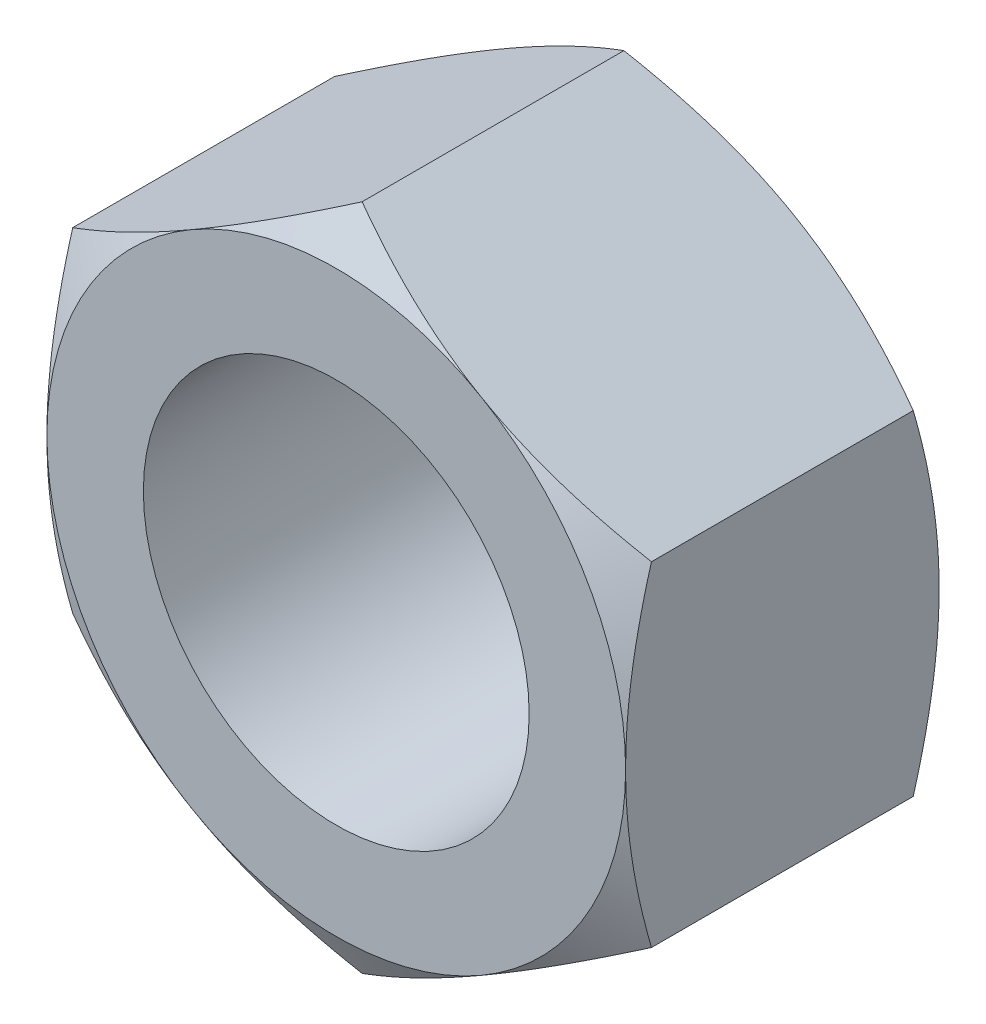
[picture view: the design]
ISO-10303-21;
HEADER;
FILE_DESCRIPTION(('STEP AP214'),'2;1');
FILE_NAME('part.step','',(''),(''),'','','');
FILE_SCHEMA(('AUTOMOTIVE_DESIGN { 1 0 10303 214 1 1 1 1 }'));
ENDSEC;
DATA;
#1=APPLICATION_CONTEXT('core data for automotive mechanical design processes');
#2=APPLICATION_PROTOCOL_DEFINITION('international standard','automotive_design',2000,#1);
#3=PRODUCT_CONTEXT('',#1,'mechanical');
#4=PRODUCT('Part','Part','',(#3));
#5=PRODUCT_RELATED_PRODUCT_CATEGORY('part','',(#4));
#6=PRODUCT_DEFINITION_FORMATION('','',#4);
#7=PRODUCT_DEFINITION_CONTEXT('part definition',#1,'design');
#8=PRODUCT_DEFINITION('design','',#6,#7);
#9=PRODUCT_DEFINITION_SHAPE('','',#8);
#10=(LENGTH_UNIT() NAMED_UNIT(*) SI_UNIT(.MILLI.,.METRE.));
#11=(NAMED_UNIT(*) PLANE_ANGLE_UNIT() SI_UNIT($,.RADIAN.));
#12=(NAMED_UNIT(*) SI_UNIT($,.STERADIAN.) SOLID_ANGLE_UNIT());
#13=UNCERTAINTY_MEASURE_WITH_UNIT(LENGTH_MEASURE(1.E-05),#10,'distance_accuracy_value','');
#14=(GEOMETRIC_REPRESENTATION_CONTEXT(3) GLOBAL_UNCERTAINTY_ASSIGNED_CONTEXT((#13)) GLOBAL_UNIT_ASSIGNED_CONTEXT((#10,
#11,#12)) REPRESENTATION_CONTEXT('',''));
#15=CARTESIAN_POINT('',(0.,0.,0.));
#16=DIRECTION('',(0.,0.,1.));
#17=DIRECTION('',(1.,0.,0.));
#18=AXIS2_PLACEMENT_3D('',#15,#16,#17);
#19=CARTESIAN_POINT('',(-12.,20.7846096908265,0.));
#20=DIRECTION('',(0.,0.,-1.));
#21=DIRECTION('',(-1.,0.,0.));
#22=AXIS2_PLACEMENT_3D('',#19,#20,#21);
#23=PLANE('',#22);
#24=CARTESIAN_POINT('',(0.,0.,0.));
#25=DIRECTION('',(0.,0.,1.));
#26=DIRECTION('',(1.,0.,0.));
#27=AXIS2_PLACEMENT_3D('',#24,#25,#26);
#28=CIRCLE('',#27,8.);
#29=CARTESIAN_POINT('',(8.,0.,0.));
#30=VERTEX_POINT('',#29);
#31=EDGE_CURVE('E318',#30,#30,#28,.T.);
#32=ORIENTED_EDGE('',*,*,#31,.F.);
#33=EDGE_LOOP('',(#32));
#34=FACE_BOUND('',#33,.T.);
#35=CARTESIAN_POINT('',(0.,0.,0.));
#36=DIRECTION('',(0.,0.,-1.));
#37=DIRECTION('',(-1.,0.,0.));
#38=AXIS2_PLACEMENT_3D('',#35,#36,#37);
#39=CIRCLE('',#38,12.);
#40=CARTESIAN_POINT('',(-12.,0.,0.));
#41=VERTEX_POINT('',#40);
#42=CARTESIAN_POINT('',(-6.,10.3923048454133,0.));
#43=VERTEX_POINT('',#42);
#44=EDGE_CURVE('E326',#41,#43,#39,.T.);
#45=ORIENTED_EDGE('',*,*,#44,.F.);
#46=CARTESIAN_POINT('',(0.,0.,0.));
#47=DIRECTION('',(0.,0.,-1.));
#48=DIRECTION('',(-1.,0.,0.));
#49=AXIS2_PLACEMENT_3D('',#46,#47,#48);
#50=CIRCLE('',#49,12.);
#51=CARTESIAN_POINT('',(-5.99999999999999,-10.3923048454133,0.));
#52=VERTEX_POINT('',#51);
#53=EDGE_CURVE('E148',#41,#52,#50,.F.);
#54=ORIENTED_EDGE('',*,*,#53,.T.);
#55=CARTESIAN_POINT('',(5.99999999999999,-10.3923048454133,0.));
#56=VERTEX_POINT('',#55);
#57=EDGE_CURVE('E250',#52,#56,#50,.F.);
#58=ORIENTED_EDGE('',*,*,#57,.T.);
#59=CARTESIAN_POINT('',(12.,0.,0.));
#60=VERTEX_POINT('',#59);
#61=EDGE_CURVE('E151',#56,#60,#50,.F.);
#62=ORIENTED_EDGE('',*,*,#61,.T.);
#63=CARTESIAN_POINT('',(5.99999999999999,10.3923048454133,0.));
#64=VERTEX_POINT('',#63);
#65=EDGE_CURVE('E126',#60,#64,#50,.F.);
#66=ORIENTED_EDGE('',*,*,#65,.T.);
#67=EDGE_CURVE('E139',#64,#43,#50,.F.);
#68=ORIENTED_EDGE('',*,*,#67,.T.);
#69=EDGE_LOOP('',(#45,#54,#58,#62,#66,#68));
#70=FACE_BOUND('',#69,.T.);
#71=ADVANCED_FACE('F31',(#34,#70),#23,.F.);
#72=CARTESIAN_POINT('',(0.,0.,0.));
#73=DIRECTION('',(0.,0.,-1.));
#74=DIRECTION('',(-1.,0.,0.));
#75=AXIS2_PLACEMENT_3D('',#72,#73,#74);
#76=CONICAL_SURFACE('',#75,12.,1.0471975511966);
#77=CARTESIAN_POINT('',(-12.,-18.6784608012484,-5.8895565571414));
#78=CARTESIAN_POINT('',(-12.,-18.4160847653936,-5.76211140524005));
#79=CARTESIAN_POINT('',(-12.,-18.1534026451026,-5.63529669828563));
#80=CARTESIAN_POINT('',(-12.,-17.6273623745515,-5.38307084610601));
#81=CARTESIAN_POINT('',(-12.,-17.3640042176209,-5.25765971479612));
#82=CARTESIAN_POINT('',(-12.,-16.5727506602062,-4.8837130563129));
#83=CARTESIAN_POINT('',(-12.,-16.0437527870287,-4.63750158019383));
#84=CARTESIAN_POINT('',(-12.,-14.9793937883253,-4.15144188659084));
#85=CARTESIAN_POINT('',(-12.,-14.444013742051,-3.91163500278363));
#86=CARTESIAN_POINT('',(-12.,-13.3690190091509,-3.44174237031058));
#87=CARTESIAN_POINT('',(-12.,-12.82940452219,-3.21165616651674));
#88=CARTESIAN_POINT('',(-12.,-11.7275565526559,-2.75653640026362));
#89=CARTESIAN_POINT('',(-12.,-11.1651555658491,-2.53190627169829));
#90=CARTESIAN_POINT('',(-12.,-10.0337957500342,-2.09948087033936));
#91=CARTESIAN_POINT('',(-12.,-9.46483619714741,-1.89168747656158));
#92=CARTESIAN_POINT('',(-12.,-8.32051465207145,-1.49834244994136));
#93=CARTESIAN_POINT('',(-12.,-7.7451680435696,-1.31274641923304));
#94=CARTESIAN_POINT('',(-12.,-6.58616859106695,-0.969694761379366));
#95=CARTESIAN_POINT('',(-12.,-6.00251840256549,-0.812230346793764));
#96=CARTESIAN_POINT('',(-12.,-5.1222851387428,-0.603216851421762));
#97=CARTESIAN_POINT('',(-12.,-4.82887752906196,-0.538215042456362));
#98=CARTESIAN_POINT('',(-12.,-4.24004478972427,-0.418045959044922));
#99=CARTESIAN_POINT('',(-12.,-3.94461970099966,-0.362878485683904));
#100=CARTESIAN_POINT('',(-12.,-3.35195163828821,-0.263347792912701));
#101=CARTESIAN_POINT('',(-12.,-3.05470869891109,-0.2189843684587));
#102=CARTESIAN_POINT('',(-12.,-2.45871340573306,-0.141943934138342));
#103=CARTESIAN_POINT('',(-12.,-2.15996111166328,-0.10926646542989));
#104=CARTESIAN_POINT('',(-12.,-1.56529773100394,-0.0566609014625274));
#105=CARTESIAN_POINT('',(-12.,-1.26940109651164,-0.0365704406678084));
#106=CARTESIAN_POINT('',(-12.,-0.67702380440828,-0.00892428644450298));
#107=CARTESIAN_POINT('',(-12.,-0.380543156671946,-0.00136838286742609));
#108=CARTESIAN_POINT('',(-12.,0.212474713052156,0.00102862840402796));
#109=CARTESIAN_POINT('',(-12.,0.509011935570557,-0.00413038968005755));
#110=CARTESIAN_POINT('',(-12.,1.10160312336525,-0.0270365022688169));
#111=CARTESIAN_POINT('',(-12.,1.39765706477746,-0.0447842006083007));
#112=CARTESIAN_POINT('',(-12.,2.1069630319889,-0.102008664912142));
#113=CARTESIAN_POINT('',(-12.,2.5197532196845,-0.147335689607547));
#114=CARTESIAN_POINT('',(-12.,3.34229647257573,-0.260007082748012));
#115=CARTESIAN_POINT('',(-12.,3.75204912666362,-0.327354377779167));
#116=CARTESIAN_POINT('',(-12.,4.97625609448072,-0.558857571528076));
#117=CARTESIAN_POINT('',(-12.,5.7852217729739,-0.752434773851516));
#118=CARTESIAN_POINT('',(-12.,6.99520122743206,-1.08852571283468));
#119=CARTESIAN_POINT('',(-12.,7.40247585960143,-1.20979800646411));
#120=CARTESIAN_POINT('',(-12.,8.21306883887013,-1.46503098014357));
#121=CARTESIAN_POINT('',(-12.,8.61638715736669,-1.59899175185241));
#122=CARTESIAN_POINT('',(-12.,9.41919631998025,-1.8774441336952));
#123=CARTESIAN_POINT('',(-12.,9.81868832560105,-2.02193242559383));
#124=CARTESIAN_POINT('',(-12.,10.6143522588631,-2.3197301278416));
#125=CARTESIAN_POINT('',(-12.,11.0105242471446,-2.47303937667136));
#126=CARTESIAN_POINT('',(-12.,12.028867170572,-2.87806719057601));
#127=CARTESIAN_POINT('',(-12.,12.6488461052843,-3.13529022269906));
#128=CARTESIAN_POINT('',(-12.,13.8828616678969,-3.66366192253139));
#129=CARTESIAN_POINT('',(-12.,14.4968977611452,-3.93481182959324));
#130=CARTESIAN_POINT('',(-12.,15.7203032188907,-4.48791421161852));
#131=CARTESIAN_POINT('',(-12.,16.3296710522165,-4.76987006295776));
#132=CARTESIAN_POINT('',(-12.,17.5444335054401,-5.34213991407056));
#133=CARTESIAN_POINT('',(-12.,18.1498282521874,-5.63245364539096));
#134=CARTESIAN_POINT('',(-12.,19.3582283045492,-6.2201156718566));
#135=CARTESIAN_POINT('',(-12.,19.9612291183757,-6.51747318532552));
#136=CARTESIAN_POINT('',(-12.,21.1645717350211,-7.11752201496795));
#137=CARTESIAN_POINT('',(-12.,21.764913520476,-7.42021336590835));
#138=CARTESIAN_POINT('',(-12.,22.9632839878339,-8.02987349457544));
#139=CARTESIAN_POINT('',(-12.,23.5613130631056,-8.33684149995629));
#140=CARTESIAN_POINT('',(-12.,24.7555248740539,-8.95434064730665));
#141=CARTESIAN_POINT('',(-12.,25.3517076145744,-9.26487177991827));
#142=CARTESIAN_POINT('',(-12.,27.0217096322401,-10.1399789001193));
#143=CARTESIAN_POINT('',(-12.,28.0937859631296,-10.7078805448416));
#144=CARTESIAN_POINT('',(-12.,30.2342410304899,-11.8507224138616));
#145=CARTESIAN_POINT('',(-12.,31.3026195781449,-12.4256629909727));
#146=CARTESIAN_POINT('',(-12.,33.4333268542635,-13.5791178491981));
#147=CARTESIAN_POINT('',(-12.,34.4956641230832,-14.1576163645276));
#148=CARTESIAN_POINT('',(-12.,36.0874641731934,-15.0283937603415));
#149=CARTESIAN_POINT('',(-12.,36.6177621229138,-15.31914802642));
#150=CARTESIAN_POINT('',(-12.,37.6778595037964,-15.901562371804));
#151=CARTESIAN_POINT('',(-12.,38.2076589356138,-16.1932224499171));
#152=CARTESIAN_POINT('',(-12.,38.7372388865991,-16.4852806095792));
#153=B_SPLINE_CURVE_WITH_KNOTS('',3,(#77,#78,#79,#80,#81,#82,#83,#84,#85,#86,#87,#88,#89,#90,
#91,#92,#93,#94,#95,#96,#97,#98,#99,#100,#101,#102,#103,#104,#105,#106,#107,#108,#109,#110,#111,
#112,#113,#114,#115,#116,#117,#118,#119,#120,#121,#122,#123,#124,#125,#126,#127,#128,#129,#130,
#131,#132,#133,#134,#135,#136,#137,#138,#139,#140,#141,#142,#143,#144,#145,#146,#147,#148,#149,
#150,#151,#152),.UNSPECIFIED.,.F.,.F.,(4,2,2,2,2,2,2,2,2,2,2,2,2,2,2,2,2,2,2,2,2,2,2,2,2,2,2,2,
2,2,2,2,2,2,2,2,2,4),(0.,0.875070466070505,1.75014960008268,3.50056350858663,5.2603893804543,
7.0201327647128,8.83673237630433,10.6535344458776,12.4666396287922,14.2791774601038,
15.1806042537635,16.0820128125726,16.9834042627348,17.8847603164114,18.7742360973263,
19.6636969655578,20.5531666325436,21.4426789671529,22.6877912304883,23.9330690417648,
26.4249371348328,27.6996687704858,28.974409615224,30.2487503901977,31.5230678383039,
33.5364846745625,35.550080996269,37.564311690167,39.5784777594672,41.5954439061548,
43.6124232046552,45.6290428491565,47.645657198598,51.2852237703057,54.9249735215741,
58.5538713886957,60.3681986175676,62.1825234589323),.UNSPECIFIED.);
#154=CARTESIAN_POINT('',(-12.,6.92820323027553,-1.07179676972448));
#155=VERTEX_POINT('',#154);
#156=EDGE_CURVE('E156',#155,#41,#153,.F.);
#157=ORIENTED_EDGE('',*,*,#156,.T.);
#158=ORIENTED_EDGE('',*,*,#44,.T.);
#159=CARTESIAN_POINT('',(0.000199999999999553,13.8565219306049,-1.07186343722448));
#160=CARTESIAN_POINT('',(-0.263585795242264,13.7042251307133,-0.983949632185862));
#161=CARTESIAN_POINT('',(-0.528355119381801,13.5513604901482,-0.900025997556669));
#162=CARTESIAN_POINT('',(-1.06001701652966,13.244405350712,-0.741266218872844));
#163=CARTESIAN_POINT('',(-1.32691025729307,13.0903144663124,-0.666433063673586));
#164=CARTESIAN_POINT('',(-2.13189040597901,12.6255589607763,-0.457017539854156));
#165=CARTESIAN_POINT('',(-2.6731550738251,12.3130596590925,-0.337903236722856));
#166=CARTESIAN_POINT('',(-3.483132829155,11.8454187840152,-0.198231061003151));
#167=CARTESIAN_POINT('',(-3.74942610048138,11.6916742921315,-0.158443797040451));
#168=CARTESIAN_POINT('',(-4.28324559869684,11.3834734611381,-0.0917233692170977));
#169=CARTESIAN_POINT('',(-4.55077184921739,11.2290171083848,-0.064790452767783));
#170=CARTESIAN_POINT('',(-5.08627036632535,10.9198468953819,-0.0244685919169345));
#171=CARTESIAN_POINT('',(-5.35424172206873,10.7651335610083,-0.0110635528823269));
#172=CARTESIAN_POINT('',(-5.89043273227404,10.4555635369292,0.00191690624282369));
#173=CARTESIAN_POINT('',(-6.15865237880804,10.3007068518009,0.00149275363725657));
#174=CARTESIAN_POINT('',(-6.66008937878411,10.0112020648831,-0.012220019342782));
#175=CARTESIAN_POINT('',(-6.89334249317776,9.87653331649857,-0.0238359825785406));
#176=CARTESIAN_POINT('',(-7.35931224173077,9.60750555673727,-0.0573080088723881));
#177=CARTESIAN_POINT('',(-7.59202883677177,9.47314656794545,-0.0791647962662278));
#178=CARTESIAN_POINT('',(-8.05679907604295,9.20481134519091,-0.132737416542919));
#179=CARTESIAN_POINT('',(-8.28885201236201,9.07083551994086,-0.164461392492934));
#180=CARTESIAN_POINT('',(-8.75186996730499,8.8035119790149,-0.237211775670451));
#181=CARTESIAN_POINT('',(-8.98283491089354,8.67016430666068,-0.278238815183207));
#182=CARTESIAN_POINT('',(-9.68394195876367,8.26537996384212,-0.416311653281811));
#183=CARTESIAN_POINT('',(-10.1520537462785,7.99511549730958,-0.527124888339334));
#184=CARTESIAN_POINT('',(-11.0812971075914,7.45861659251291,-0.778625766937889));
#185=CARTESIAN_POINT('',(-11.5424405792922,7.19237528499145,-0.919254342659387));
#186=CARTESIAN_POINT('',(-12.0002,6.92808776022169,-1.07186343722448));
#187=B_SPLINE_CURVE_WITH_KNOTS('',3,(#159,#160,#161,#162,#163,#164,#165,#166,#167,#168,#169,
#170,#171,#172,#173,#174,#175,#176,#177,#178,#179,#180,#181,#182,#183,#184,#185,#186),
.UNSPECIFIED.,.F.,.F.,(4,2,2,2,2,2,2,2,2,2,2,2,2,4),(0.,0.951004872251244,1.90232158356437,
3.80900466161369,4.7389455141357,5.66890426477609,6.59775529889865,7.5265776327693,
8.33514643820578,9.14377244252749,9.95306755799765,10.7624176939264,12.4167102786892,
14.0677556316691),.UNSPECIFIED.);
#188=EDGE_CURVE('E188',#43,#155,#187,.T.);
#189=ORIENTED_EDGE('',*,*,#188,.T.);
#190=EDGE_LOOP('',(#157,#158,#189));
#191=FACE_BOUND('',#190,.T.);
#192=ADVANCED_FACE('F175',(#191),#76,.T.);
#193=CARTESIAN_POINT('',(12.0002,6.92808776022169,-1.07186343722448));
#194=CARTESIAN_POINT('',(11.7364142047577,7.08038456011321,-0.983949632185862));
#195=CARTESIAN_POINT('',(11.4716448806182,7.23324920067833,-0.900025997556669));
#196=CARTESIAN_POINT('',(10.9399829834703,7.54020434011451,-0.741266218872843));
#197=CARTESIAN_POINT('',(10.6730897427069,7.69429522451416,-0.666433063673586));
#198=CARTESIAN_POINT('',(9.86810959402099,8.15905073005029,-0.457017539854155));
#199=CARTESIAN_POINT('',(9.3268449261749,8.47155003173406,-0.337903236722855));
#200=CARTESIAN_POINT('',(8.516867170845,8.93919090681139,-0.198231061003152));
#201=CARTESIAN_POINT('',(8.25057389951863,9.09293539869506,-0.158443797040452));
#202=CARTESIAN_POINT('',(7.71675440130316,9.40113622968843,-0.0917233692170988));
#203=CARTESIAN_POINT('',(7.44922815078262,9.55559258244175,-0.0647904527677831));
#204=CARTESIAN_POINT('',(6.91372963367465,9.86476279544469,-0.0244685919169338));
#205=CARTESIAN_POINT('',(6.64575827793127,10.0194761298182,-0.0110635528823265));
#206=CARTESIAN_POINT('',(6.10956726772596,10.3290461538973,0.00191690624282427));
#207=CARTESIAN_POINT('',(5.84134762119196,10.4839028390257,0.00149275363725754));
#208=CARTESIAN_POINT('',(5.33991062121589,10.7734076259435,-0.0122200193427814));
#209=CARTESIAN_POINT('',(5.10665750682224,10.908076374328,-0.0238359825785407));
#210=CARTESIAN_POINT('',(4.64068775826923,11.1771041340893,-0.0573080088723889));
#211=CARTESIAN_POINT('',(4.40797116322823,11.3114631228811,-0.0791647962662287));
#212=CARTESIAN_POINT('',(3.94320092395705,11.5797983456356,-0.13273741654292));
#213=CARTESIAN_POINT('',(3.71114798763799,11.7137741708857,-0.164461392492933));
#214=CARTESIAN_POINT('',(3.24813003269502,11.9810977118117,-0.23721177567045));
#215=CARTESIAN_POINT('',(3.01716508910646,12.1144453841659,-0.278238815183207));
#216=CARTESIAN_POINT('',(2.31605804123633,12.5192297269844,-0.416311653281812));
#217=CARTESIAN_POINT('',(1.84794625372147,12.789494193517,-0.527124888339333));
#218=CARTESIAN_POINT('',(0.918702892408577,13.3259930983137,-0.778625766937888));
#219=CARTESIAN_POINT('',(0.457559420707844,13.5922344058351,-0.919254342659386));
#220=CARTESIAN_POINT('',(-0.000199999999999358,13.8565219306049,-1.07186343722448));
#221=B_SPLINE_CURVE_WITH_KNOTS('',3,(#193,#194,#195,#196,#197,#198,#199,#200,#201,#202,#203,
#204,#205,#206,#207,#208,#209,#210,#211,#212,#213,#214,#215,#216,#217,#218,#219,#220),
.UNSPECIFIED.,.F.,.F.,(4,2,2,2,2,2,2,2,2,2,2,2,2,4),(0.,0.951004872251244,1.90232158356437,
3.80900466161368,4.7389455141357,5.66890426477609,6.59775529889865,7.5265776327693,
8.33514643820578,9.14377244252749,9.95306755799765,10.7624176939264,12.4167102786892,
14.0677556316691),.UNSPECIFIED.);
#222=CARTESIAN_POINT('',(0.,13.856406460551,-1.07179676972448));
#223=VERTEX_POINT('',#222);
#224=EDGE_CURVE('E135',#64,#223,#221,.T.);
#225=ORIENTED_EDGE('',*,*,#224,.T.);
#226=EDGE_CURVE('E142',#223,#43,#187,.T.);
#227=ORIENTED_EDGE('',*,*,#226,.T.);
#228=ORIENTED_EDGE('',*,*,#67,.F.);
#229=EDGE_LOOP('',(#225,#227,#228));
#230=FACE_BOUND('',#229,.T.);
#231=ADVANCED_FACE('F140',(#230),#76,.T.);
#232=CARTESIAN_POINT('',(12.,-18.6784608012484,-5.8895565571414));
#233=CARTESIAN_POINT('',(12.,-18.4160847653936,-5.76211140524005));
#234=CARTESIAN_POINT('',(12.,-18.1534026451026,-5.63529669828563));
#235=CARTESIAN_POINT('',(12.,-17.6273623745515,-5.38307084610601));
#236=CARTESIAN_POINT('',(12.,-17.3640042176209,-5.25765971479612));
#237=CARTESIAN_POINT('',(12.,-16.5727506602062,-4.8837130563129));
#238=CARTESIAN_POINT('',(12.,-16.0437527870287,-4.63750158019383));
#239=CARTESIAN_POINT('',(12.,-14.9793937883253,-4.15144188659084));
#240=CARTESIAN_POINT('',(12.,-14.444013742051,-3.91163500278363));
#241=CARTESIAN_POINT('',(12.,-13.3690190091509,-3.44174237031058));
#242=CARTESIAN_POINT('',(12.,-12.82940452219,-3.21165616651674));
#243=CARTESIAN_POINT('',(12.,-11.7275565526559,-2.75653640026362));
#244=CARTESIAN_POINT('',(12.,-11.1651555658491,-2.53190627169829));
#245=CARTESIAN_POINT('',(12.,-10.0337957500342,-2.09948087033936));
#246=CARTESIAN_POINT('',(12.,-9.46483619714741,-1.89168747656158));
#247=CARTESIAN_POINT('',(12.,-8.32051465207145,-1.49834244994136));
#248=CARTESIAN_POINT('',(12.,-7.7451680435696,-1.31274641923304));
#249=CARTESIAN_POINT('',(12.,-6.58616859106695,-0.969694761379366));
#250=CARTESIAN_POINT('',(12.,-6.00251840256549,-0.812230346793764));
#251=CARTESIAN_POINT('',(12.,-5.1222851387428,-0.603216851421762));
#252=CARTESIAN_POINT('',(12.,-4.82887752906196,-0.538215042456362));
#253=CARTESIAN_POINT('',(12.,-4.24004478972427,-0.418045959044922));
#254=CARTESIAN_POINT('',(12.,-3.94461970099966,-0.362878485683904));
#255=CARTESIAN_POINT('',(12.,-3.35195163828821,-0.263347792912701));
#256=CARTESIAN_POINT('',(12.,-3.05470869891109,-0.2189843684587));
#257=CARTESIAN_POINT('',(12.,-2.45871340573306,-0.141943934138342));
#258=CARTESIAN_POINT('',(12.,-2.15996111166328,-0.10926646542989));
#259=CARTESIAN_POINT('',(12.,-1.56529773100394,-0.0566609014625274));
#260=CARTESIAN_POINT('',(12.,-1.26940109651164,-0.0365704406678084));
#261=CARTESIAN_POINT('',(12.,-0.67702380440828,-0.00892428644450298));
#262=CARTESIAN_POINT('',(12.,-0.380543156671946,-0.00136838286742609));
#263=CARTESIAN_POINT('',(12.,0.212474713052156,0.00102862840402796));
#264=CARTESIAN_POINT('',(12.,0.509011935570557,-0.00413038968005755));
#265=CARTESIAN_POINT('',(12.,1.10160312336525,-0.0270365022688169));
#266=CARTESIAN_POINT('',(12.,1.39765706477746,-0.0447842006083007));
#267=CARTESIAN_POINT('',(12.,2.1069630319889,-0.102008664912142));
#268=CARTESIAN_POINT('',(12.,2.5197532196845,-0.147335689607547));
#269=CARTESIAN_POINT('',(12.,3.34229647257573,-0.260007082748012));
#270=CARTESIAN_POINT('',(12.,3.75204912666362,-0.327354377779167));
#271=CARTESIAN_POINT('',(12.,4.97625609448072,-0.558857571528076));
#272=CARTESIAN_POINT('',(12.,5.7852217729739,-0.752434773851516));
#273=CARTESIAN_POINT('',(12.,6.99520122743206,-1.08852571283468));
#274=CARTESIAN_POINT('',(12.,7.40247585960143,-1.20979800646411));
#275=CARTESIAN_POINT('',(12.,8.21306883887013,-1.46503098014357));
#276=CARTESIAN_POINT('',(12.,8.61638715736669,-1.59899175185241));
#277=CARTESIAN_POINT('',(12.,9.41919631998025,-1.8774441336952));
#278=CARTESIAN_POINT('',(12.,9.81868832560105,-2.02193242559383));
#279=CARTESIAN_POINT('',(12.,10.6143522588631,-2.3197301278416));
#280=CARTESIAN_POINT('',(12.,11.0105242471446,-2.47303937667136));
#281=CARTESIAN_POINT('',(12.,12.028867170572,-2.87806719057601));
#282=CARTESIAN_POINT('',(12.,12.6488461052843,-3.13529022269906));
#283=CARTESIAN_POINT('',(12.,13.8828616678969,-3.66366192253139));
#284=CARTESIAN_POINT('',(12.,14.4968977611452,-3.93481182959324));
#285=CARTESIAN_POINT('',(12.,15.7203032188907,-4.48791421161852));
#286=CARTESIAN_POINT('',(12.,16.3296710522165,-4.76987006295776));
#287=CARTESIAN_POINT('',(12.,17.5444335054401,-5.34213991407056));
#288=CARTESIAN_POINT('',(12.,18.1498282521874,-5.63245364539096));
#289=CARTESIAN_POINT('',(12.,19.3582283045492,-6.2201156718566));
#290=CARTESIAN_POINT('',(12.,19.9612291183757,-6.51747318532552));
#291=CARTESIAN_POINT('',(12.,21.1645717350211,-7.11752201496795));
#292=CARTESIAN_POINT('',(12.,21.764913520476,-7.42021336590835));
#293=CARTESIAN_POINT('',(12.,22.9632839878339,-8.02987349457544));
#294=CARTESIAN_POINT('',(12.,23.5613130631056,-8.33684149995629));
#295=CARTESIAN_POINT('',(12.,24.7555248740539,-8.95434064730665));
#296=CARTESIAN_POINT('',(12.,25.3517076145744,-9.26487177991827));
#297=CARTESIAN_POINT('',(12.,27.0217096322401,-10.1399789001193));
#298=CARTESIAN_POINT('',(12.,28.0937859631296,-10.7078805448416));
#299=CARTESIAN_POINT('',(12.,30.2342410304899,-11.8507224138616));
#300=CARTESIAN_POINT('',(12.,31.3026195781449,-12.4256629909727));
#301=CARTESIAN_POINT('',(12.,33.4333268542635,-13.5791178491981));
#302=CARTESIAN_POINT('',(12.,34.4956641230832,-14.1576163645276));
#303=CARTESIAN_POINT('',(12.,36.0874641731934,-15.0283937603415));
#304=CARTESIAN_POINT('',(12.,36.6177621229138,-15.31914802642));
#305=CARTESIAN_POINT('',(12.,37.6778595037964,-15.901562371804));
#306=CARTESIAN_POINT('',(12.,38.2076589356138,-16.1932224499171));
#307=CARTESIAN_POINT('',(12.,38.7372388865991,-16.4852806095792));
#308=B_SPLINE_CURVE_WITH_KNOTS('',3,(#232,#233,#234,#235,#236,#237,#238,#239,#240,#241,#242,
#243,#244,#245,#246,#247,#248,#249,#250,#251,#252,#253,#254,#255,#256,#257,#258,#259,#260,#261,
#262,#263,#264,#265,#266,#267,#268,#269,#270,#271,#272,#273,#274,#275,#276,#277,#278,#279,#280,
#281,#282,#283,#284,#285,#286,#287,#288,#289,#290,#291,#292,#293,#294,#295,#296,#297,#298,#299,
#300,#301,#302,#303,#304,#305,#306,#307),.UNSPECIFIED.,.F.,.F.,(4,2,2,2,2,2,2,2,2,2,2,2,2,2,2,2,
2,2,2,2,2,2,2,2,2,2,2,2,2,2,2,2,2,2,2,2,2,4),(0.,0.875070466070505,1.75014960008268,
3.50056350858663,5.2603893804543,7.0201327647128,8.83673237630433,10.6535344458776,
12.4666396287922,14.2791774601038,15.1806042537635,16.0820128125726,16.9834042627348,
17.8847603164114,18.7742360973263,19.6636969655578,20.5531666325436,21.4426789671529,
22.6877912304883,23.9330690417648,26.4249371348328,27.6996687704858,28.974409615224,
30.2487503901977,31.5230678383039,33.5364846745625,35.550080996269,37.564311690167,
39.5784777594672,41.5954439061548,43.6124232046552,45.6290428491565,47.645657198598,
51.2852237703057,54.9249735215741,58.5538713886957,60.3681986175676,62.1825234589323),.UNSPECIFIED.);
#309=CARTESIAN_POINT('',(12.,6.92820323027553,-1.07179676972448));
#310=VERTEX_POINT('',#309);
#311=EDGE_CURVE('E129',#60,#310,#308,.T.);
#312=ORIENTED_EDGE('',*,*,#311,.T.);
#313=EDGE_CURVE('E122',#310,#64,#221,.T.);
#314=ORIENTED_EDGE('',*,*,#313,.T.);
#315=ORIENTED_EDGE('',*,*,#65,.F.);
#316=EDGE_LOOP('',(#312,#314,#315));
#317=FACE_BOUND('',#316,.T.);
#318=ADVANCED_FACE('F124',(#317),#76,.T.);
#319=CARTESIAN_POINT('',(-0.000199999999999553,-13.8565219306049,-1.07186343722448));
#320=CARTESIAN_POINT('',(0.263585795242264,-13.7042251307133,-0.983949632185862));
#321=CARTESIAN_POINT('',(0.528355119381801,-13.5513604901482,-0.900025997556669));
#322=CARTESIAN_POINT('',(1.06001701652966,-13.244405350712,-0.741266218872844));
#323=CARTESIAN_POINT('',(1.32691025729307,-13.0903144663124,-0.666433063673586));
#324=CARTESIAN_POINT('',(2.13189040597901,-12.6255589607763,-0.457017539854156));
#325=CARTESIAN_POINT('',(2.6731550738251,-12.3130596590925,-0.337903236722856));
#326=CARTESIAN_POINT('',(3.483132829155,-11.8454187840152,-0.198231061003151));
#327=CARTESIAN_POINT('',(3.74942610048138,-11.6916742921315,-0.158443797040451));
#328=CARTESIAN_POINT('',(4.28324559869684,-11.3834734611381,-0.0917233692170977));
#329=CARTESIAN_POINT('',(4.55077184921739,-11.2290171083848,-0.064790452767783));
#330=CARTESIAN_POINT('',(5.08627036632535,-10.9198468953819,-0.0244685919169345));
#331=CARTESIAN_POINT('',(5.35424172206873,-10.7651335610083,-0.0110635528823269));
#332=CARTESIAN_POINT('',(5.89043273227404,-10.4555635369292,0.00191690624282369));
#333=CARTESIAN_POINT('',(6.15865237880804,-10.3007068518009,0.00149275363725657));
#334=CARTESIAN_POINT('',(6.66008937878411,-10.0112020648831,-0.012220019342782));
#335=CARTESIAN_POINT('',(6.89334249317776,-9.87653331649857,-0.0238359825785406));
#336=CARTESIAN_POINT('',(7.35931224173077,-9.60750555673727,-0.0573080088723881));
#337=CARTESIAN_POINT('',(7.59202883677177,-9.47314656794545,-0.0791647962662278));
#338=CARTESIAN_POINT('',(8.05679907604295,-9.20481134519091,-0.132737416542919));
#339=CARTESIAN_POINT('',(8.28885201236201,-9.07083551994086,-0.164461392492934));
#340=CARTESIAN_POINT('',(8.75186996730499,-8.8035119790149,-0.237211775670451));
#341=CARTESIAN_POINT('',(8.98283491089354,-8.67016430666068,-0.278238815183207));
#342=CARTESIAN_POINT('',(9.68394195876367,-8.26537996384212,-0.416311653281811));
#343=CARTESIAN_POINT('',(10.1520537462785,-7.99511549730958,-0.527124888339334));
#344=CARTESIAN_POINT('',(11.0812971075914,-7.45861659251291,-0.778625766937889));
#345=CARTESIAN_POINT('',(11.5424405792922,-7.19237528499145,-0.919254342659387));
#346=CARTESIAN_POINT('',(12.0002,-6.92808776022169,-1.07186343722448));
#347=B_SPLINE_CURVE_WITH_KNOTS('',3,(#319,#320,#321,#322,#323,#324,#325,#326,#327,#328,#329,
#330,#331,#332,#333,#334,#335,#336,#337,#338,#339,#340,#341,#342,#343,#344,#345,#346),
.UNSPECIFIED.,.F.,.F.,(4,2,2,2,2,2,2,2,2,2,2,2,2,4),(0.,0.951004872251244,1.90232158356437,
3.80900466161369,4.7389455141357,5.66890426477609,6.59775529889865,7.5265776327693,
8.33514643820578,9.14377244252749,9.95306755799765,10.7624176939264,12.4167102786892,
14.0677556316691),.UNSPECIFIED.);
#348=CARTESIAN_POINT('',(12.,-6.92820323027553,-1.07179676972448));
#349=VERTEX_POINT('',#348);
#350=EDGE_CURVE('E202',#56,#349,#347,.T.);
#351=ORIENTED_EDGE('',*,*,#350,.T.);
#352=EDGE_CURVE('E201',#349,#60,#308,.T.);
#353=ORIENTED_EDGE('',*,*,#352,.T.);
#354=ORIENTED_EDGE('',*,*,#61,.F.);
#355=EDGE_LOOP('',(#351,#353,#354));
#356=FACE_BOUND('',#355,.T.);
#357=ADVANCED_FACE('F426',(#356),#76,.T.);
#358=CARTESIAN_POINT('',(0.,-13.856406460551,-1.07179676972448));
#359=VERTEX_POINT('',#358);
#360=EDGE_CURVE('E260',#359,#56,#347,.T.);
#361=ORIENTED_EDGE('',*,*,#360,.T.);
#362=ORIENTED_EDGE('',*,*,#57,.F.);
#363=CARTESIAN_POINT('',(-12.0002,-6.92808776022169,-1.07186343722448));
#364=CARTESIAN_POINT('',(-11.7364142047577,-7.08038456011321,-0.983949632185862));
#365=CARTESIAN_POINT('',(-11.4716448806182,-7.23324920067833,-0.900025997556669));
#366=CARTESIAN_POINT('',(-10.9399829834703,-7.54020434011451,-0.741266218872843));
#367=CARTESIAN_POINT('',(-10.6730897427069,-7.69429522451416,-0.666433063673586));
#368=CARTESIAN_POINT('',(-9.86810959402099,-8.15905073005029,-0.457017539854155));
#369=CARTESIAN_POINT('',(-9.3268449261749,-8.47155003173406,-0.337903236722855));
#370=CARTESIAN_POINT('',(-8.516867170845,-8.93919090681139,-0.198231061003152));
#371=CARTESIAN_POINT('',(-8.25057389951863,-9.09293539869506,-0.158443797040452));
#372=CARTESIAN_POINT('',(-7.71675440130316,-9.40113622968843,-0.0917233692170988));
#373=CARTESIAN_POINT('',(-7.44922815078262,-9.55559258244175,-0.0647904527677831));
#374=CARTESIAN_POINT('',(-6.91372963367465,-9.86476279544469,-0.0244685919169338));
#375=CARTESIAN_POINT('',(-6.64575827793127,-10.0194761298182,-0.0110635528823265));
#376=CARTESIAN_POINT('',(-6.10956726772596,-10.3290461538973,0.00191690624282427));
#377=CARTESIAN_POINT('',(-5.84134762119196,-10.4839028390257,0.00149275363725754));
#378=CARTESIAN_POINT('',(-5.33991062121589,-10.7734076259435,-0.0122200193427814));
#379=CARTESIAN_POINT('',(-5.10665750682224,-10.908076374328,-0.0238359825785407));
#380=CARTESIAN_POINT('',(-4.64068775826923,-11.1771041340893,-0.0573080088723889));
#381=CARTESIAN_POINT('',(-4.40797116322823,-11.3114631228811,-0.0791647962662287));
#382=CARTESIAN_POINT('',(-3.94320092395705,-11.5797983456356,-0.13273741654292));
#383=CARTESIAN_POINT('',(-3.71114798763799,-11.7137741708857,-0.164461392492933));
#384=CARTESIAN_POINT('',(-3.24813003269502,-11.9810977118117,-0.23721177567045));
#385=CARTESIAN_POINT('',(-3.01716508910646,-12.1144453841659,-0.278238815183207));
#386=CARTESIAN_POINT('',(-2.31605804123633,-12.5192297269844,-0.416311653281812));
#387=CARTESIAN_POINT('',(-1.84794625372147,-12.789494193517,-0.527124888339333));
#388=CARTESIAN_POINT('',(-0.918702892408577,-13.3259930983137,-0.778625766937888));
#389=CARTESIAN_POINT('',(-0.457559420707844,-13.5922344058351,-0.919254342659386));
#390=CARTESIAN_POINT('',(0.000199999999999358,-13.8565219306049,-1.07186343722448));
#391=B_SPLINE_CURVE_WITH_KNOTS('',3,(#363,#364,#365,#366,#367,#368,#369,#370,#371,#372,#373,
#374,#375,#376,#377,#378,#379,#380,#381,#382,#383,#384,#385,#386,#387,#388,#389,#390),
.UNSPECIFIED.,.F.,.F.,(4,2,2,2,2,2,2,2,2,2,2,2,2,4),(0.,0.951004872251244,1.90232158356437,
3.80900466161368,4.7389455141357,5.66890426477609,6.59775529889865,7.5265776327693,
8.33514643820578,9.14377244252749,9.95306755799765,10.7624176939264,12.4167102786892,
14.0677556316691),.UNSPECIFIED.);
#392=EDGE_CURVE('E264',#52,#359,#391,.T.);
#393=ORIENTED_EDGE('',*,*,#392,.T.);
#394=EDGE_LOOP('',(#361,#362,#393));
#395=FACE_BOUND('',#394,.T.);
#396=ADVANCED_FACE('F181',(#395),#76,.T.);
#397=CARTESIAN_POINT('',(-12.,-6.92820323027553,-1.07179676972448));
#398=VERTEX_POINT('',#397);
#399=EDGE_CURVE('E169',#398,#52,#391,.T.);
#400=ORIENTED_EDGE('',*,*,#399,.T.);
#401=ORIENTED_EDGE('',*,*,#53,.F.);
#402=EDGE_CURVE('E134',#41,#398,#153,.F.);
#403=ORIENTED_EDGE('',*,*,#402,.T.);
#404=EDGE_LOOP('',(#400,#401,#403));
#405=FACE_BOUND('',#404,.T.);
#406=ADVANCED_FACE('F269',(#405),#76,.T.);
#407=CARTESIAN_POINT('',(12.,6.92820323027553,-13.));
#408=DIRECTION('',(0.5,0.866025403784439,0.));
#409=DIRECTION('',(-0.866025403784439,0.5,0.));
#410=AXIS2_PLACEMENT_3D('',#407,#408,#409);
#411=PLANE('',#410);
#412=CARTESIAN_POINT('',(-0.0002,13.8565219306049,-11.9281365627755));
#413=CARTESIAN_POINT('',(0.263585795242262,13.7042251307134,-12.0160503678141));
#414=CARTESIAN_POINT('',(0.5283551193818,13.5513604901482,-12.0999740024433));
#415=CARTESIAN_POINT('',(1.06001701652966,13.244405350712,-12.2587337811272));
#416=CARTESIAN_POINT('',(1.32691025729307,13.0903144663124,-12.3335669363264));
#417=CARTESIAN_POINT('',(2.13189040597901,12.6255589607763,-12.5429824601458));
#418=CARTESIAN_POINT('',(2.6731550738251,12.3130596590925,-12.6620967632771));
#419=CARTESIAN_POINT('',(3.483132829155,11.8454187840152,-12.8017689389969));
#420=CARTESIAN_POINT('',(3.74942610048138,11.6916742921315,-12.8415562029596));
#421=CARTESIAN_POINT('',(4.28324559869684,11.3834734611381,-12.9082766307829));
#422=CARTESIAN_POINT('',(4.55077184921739,11.2290171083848,-12.9352095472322));
#423=CARTESIAN_POINT('',(5.08627036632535,10.9198468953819,-12.9755314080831));
#424=CARTESIAN_POINT('',(5.35424172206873,10.7651335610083,-12.9889364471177));
#425=CARTESIAN_POINT('',(5.89043273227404,10.4555635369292,-13.0019169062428));
#426=CARTESIAN_POINT('',(6.15865237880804,10.3007068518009,-13.0014927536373));
#427=CARTESIAN_POINT('',(6.66008937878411,10.0112020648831,-12.9877799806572));
#428=CARTESIAN_POINT('',(6.89334249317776,9.87653331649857,-12.9761640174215));
#429=CARTESIAN_POINT('',(7.35931224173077,9.60750555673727,-12.9426919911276));
#430=CARTESIAN_POINT('',(7.59202883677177,9.47314656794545,-12.9208352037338));
#431=CARTESIAN_POINT('',(8.05679907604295,9.20481134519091,-12.8672625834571));
#432=CARTESIAN_POINT('',(8.28885201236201,9.07083551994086,-12.8355386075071));
#433=CARTESIAN_POINT('',(8.75186996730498,8.80351197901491,-12.7627882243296));
#434=CARTESIAN_POINT('',(8.98283491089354,8.67016430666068,-12.7217611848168));
#435=CARTESIAN_POINT('',(9.68394195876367,8.26537996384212,-12.5836883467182));
#436=CARTESIAN_POINT('',(10.1520537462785,7.99511549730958,-12.4728751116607));
#437=CARTESIAN_POINT('',(11.0812971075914,7.45861659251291,-12.2213742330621));
#438=CARTESIAN_POINT('',(11.5424405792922,7.19237528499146,-12.0807456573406));
#439=CARTESIAN_POINT('',(12.0002,6.92808776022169,-11.9281365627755));
#440=B_SPLINE_CURVE_WITH_KNOTS('',3,(#412,#413,#414,#415,#416,#417,#418,#419,#420,#421,#422,
#423,#424,#425,#426,#427,#428,#429,#430,#431,#432,#433,#434,#435,#436,#437,#438,#439),
.UNSPECIFIED.,.F.,.F.,(4,2,2,2,2,2,2,2,2,2,2,2,2,4),(0.,0.951004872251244,1.90232158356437,
3.80900466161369,4.7389455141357,5.66890426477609,6.59775529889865,7.5265776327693,
8.33514643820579,9.14377244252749,9.95306755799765,10.7624176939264,12.4167102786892,
14.0677556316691),.UNSPECIFIED.);
#441=CARTESIAN_POINT('',(0.,13.856406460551,-11.9282032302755));
#442=VERTEX_POINT('',#441);
#443=CARTESIAN_POINT('',(5.99999999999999,10.3923048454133,-13.));
#444=VERTEX_POINT('',#443);
#445=EDGE_CURVE('E235',#442,#444,#440,.T.);
#446=ORIENTED_EDGE('',*,*,#445,.F.);
#447=DIRECTION('',(0.,0.,1.));
#448=VECTOR('',#447,1.);
#449=CARTESIAN_POINT('',(0.,13.856406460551,-13.));
#450=LINE('',#449,#448);
#451=EDGE_CURVE('E155',#442,#223,#450,.T.);
#452=ORIENTED_EDGE('',*,*,#451,.T.);
#453=ORIENTED_EDGE('',*,*,#224,.F.);
#454=ORIENTED_EDGE('',*,*,#313,.F.);
#455=DIRECTION('',(0.,0.,1.));
#456=VECTOR('',#455,1.);
#457=CARTESIAN_POINT('',(12.,6.92820323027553,-13.));
#458=LINE('',#457,#456);
#459=CARTESIAN_POINT('',(12.,6.92820323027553,-11.9282032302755));
#460=VERTEX_POINT('',#459);
#461=EDGE_CURVE('E147',#460,#310,#458,.T.);
#462=ORIENTED_EDGE('',*,*,#461,.F.);
#463=EDGE_CURVE('E230',#444,#460,#440,.T.);
#464=ORIENTED_EDGE('',*,*,#463,.F.);
#465=EDGE_LOOP('',(#446,#452,#453,#454,#462,#464));
#466=FACE_BOUND('',#465,.T.);
#467=ADVANCED_FACE('F33',(#466),#411,.T.);
#468=CARTESIAN_POINT('',(12.,-6.92820323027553,-13.));
#469=DIRECTION('',(1.,0.,0.));
#470=DIRECTION('',(0.,0.,-1.));
#471=AXIS2_PLACEMENT_3D('',#468,#469,#470);
#472=PLANE('',#471);
#473=CARTESIAN_POINT('',(12.,-18.6784608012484,-7.1104434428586));
#474=CARTESIAN_POINT('',(12.,-18.4160847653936,-7.23788859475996));
#475=CARTESIAN_POINT('',(12.,-18.1534026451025,-7.36470330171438));
#476=CARTESIAN_POINT('',(12.,-17.6273623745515,-7.616929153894));
#477=CARTESIAN_POINT('',(12.,-17.3640042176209,-7.74234028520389));
#478=CARTESIAN_POINT('',(12.,-16.5727506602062,-8.11628694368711));
#479=CARTESIAN_POINT('',(12.,-16.0437527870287,-8.36249841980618));
#480=CARTESIAN_POINT('',(12.,-14.9793937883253,-8.84855811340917));
#481=CARTESIAN_POINT('',(12.,-14.444013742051,-9.08836499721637));
#482=CARTESIAN_POINT('',(12.,-13.3690190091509,-9.55825762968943));
#483=CARTESIAN_POINT('',(12.,-12.82940452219,-9.78834383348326));
#484=CARTESIAN_POINT('',(12.,-11.7275565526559,-10.2434635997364));
#485=CARTESIAN_POINT('',(12.,-11.1651555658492,-10.4680937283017));
#486=CARTESIAN_POINT('',(12.,-10.0337957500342,-10.9005191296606));
#487=CARTESIAN_POINT('',(12.,-9.46483619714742,-11.1083125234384));
#488=CARTESIAN_POINT('',(12.,-8.32051465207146,-11.5016575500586));
#489=CARTESIAN_POINT('',(12.,-7.74516804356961,-11.687253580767));
#490=CARTESIAN_POINT('',(12.,-6.58616859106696,-12.0303052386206));
#491=CARTESIAN_POINT('',(12.,-6.0025184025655,-12.1877696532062));
#492=CARTESIAN_POINT('',(12.,-5.12228513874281,-12.3967831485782));
#493=CARTESIAN_POINT('',(12.,-4.82887752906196,-12.4617849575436));
#494=CARTESIAN_POINT('',(12.,-4.24004478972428,-12.5819540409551));
#495=CARTESIAN_POINT('',(12.,-3.94461970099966,-12.6371215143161));
#496=CARTESIAN_POINT('',(12.,-3.35195163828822,-12.7366522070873));
#497=CARTESIAN_POINT('',(12.,-3.05470869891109,-12.7810156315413));
#498=CARTESIAN_POINT('',(12.,-2.45871340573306,-12.8580560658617));
#499=CARTESIAN_POINT('',(12.,-2.15996111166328,-12.8907335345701));
#500=CARTESIAN_POINT('',(12.,-1.56529773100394,-12.9433390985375));
#501=CARTESIAN_POINT('',(12.,-1.26940109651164,-12.9634295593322));
#502=CARTESIAN_POINT('',(12.,-0.677023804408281,-12.9910757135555));
#503=CARTESIAN_POINT('',(12.,-0.380543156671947,-12.9986316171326));
#504=CARTESIAN_POINT('',(12.,0.212474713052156,-13.001028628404));
#505=CARTESIAN_POINT('',(12.,0.509011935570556,-12.9958696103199));
#506=CARTESIAN_POINT('',(12.,1.10160312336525,-12.9729634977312));
#507=CARTESIAN_POINT('',(12.,1.39765706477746,-12.9552157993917));
#508=CARTESIAN_POINT('',(12.,2.1069630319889,-12.8979913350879));
#509=CARTESIAN_POINT('',(12.,2.5197532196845,-12.8526643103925));
#510=CARTESIAN_POINT('',(12.,3.34229647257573,-12.739992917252));
#511=CARTESIAN_POINT('',(12.,3.75204912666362,-12.6726456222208));
#512=CARTESIAN_POINT('',(12.,4.97625609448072,-12.4411424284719));
#513=CARTESIAN_POINT('',(12.,5.78522177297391,-12.2475652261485));
#514=CARTESIAN_POINT('',(12.,6.99520122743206,-11.9114742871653));
#515=CARTESIAN_POINT('',(12.,7.40247585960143,-11.7902019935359));
#516=CARTESIAN_POINT('',(12.,8.21306883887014,-11.5349690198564));
#517=CARTESIAN_POINT('',(12.,8.61638715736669,-11.4010082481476));
#518=CARTESIAN_POINT('',(12.,9.41919631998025,-11.1225558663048));
#519=CARTESIAN_POINT('',(12.,9.81868832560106,-10.9780675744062));
#520=CARTESIAN_POINT('',(12.,10.6143522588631,-10.6802698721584));
#521=CARTESIAN_POINT('',(12.,11.0105242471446,-10.5269606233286));
#522=CARTESIAN_POINT('',(12.,12.028867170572,-10.121932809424));
#523=CARTESIAN_POINT('',(12.,12.6488461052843,-9.86470977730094));
#524=CARTESIAN_POINT('',(12.,13.8828616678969,-9.33633807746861));
#525=CARTESIAN_POINT('',(12.,14.4968977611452,-9.06518817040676));
#526=CARTESIAN_POINT('',(12.,15.7203032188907,-8.51208578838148));
#527=CARTESIAN_POINT('',(12.,16.3296710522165,-8.23012993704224));
#528=CARTESIAN_POINT('',(12.,17.5444335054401,-7.65786008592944));
#529=CARTESIAN_POINT('',(12.,18.1498282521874,-7.36754635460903));
#530=CARTESIAN_POINT('',(12.,19.3582283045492,-6.7798843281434));
#531=CARTESIAN_POINT('',(12.,19.9612291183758,-6.48252681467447));
#532=CARTESIAN_POINT('',(12.,21.1645717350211,-5.88247798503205));
#533=CARTESIAN_POINT('',(12.,21.764913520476,-5.57978663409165));
#534=CARTESIAN_POINT('',(12.,22.9632839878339,-4.97012650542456));
#535=CARTESIAN_POINT('',(12.,23.5613130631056,-4.6631585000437));
#536=CARTESIAN_POINT('',(12.,24.7555248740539,-4.04565935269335));
#537=CARTESIAN_POINT('',(12.,25.3517076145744,-3.73512822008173));
#538=CARTESIAN_POINT('',(12.,27.0217096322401,-2.86002109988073));
#539=CARTESIAN_POINT('',(12.,28.0937859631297,-2.29211945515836));
#540=CARTESIAN_POINT('',(12.,30.2342410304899,-1.14927758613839));
#541=CARTESIAN_POINT('',(12.,31.3026195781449,-0.574337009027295));
#542=CARTESIAN_POINT('',(12.,33.4333268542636,0.579117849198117));
#543=CARTESIAN_POINT('',(12.,34.4956641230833,1.15761636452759));
#544=CARTESIAN_POINT('',(12.,36.0874641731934,2.02839376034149));
#545=CARTESIAN_POINT('',(12.,36.6177621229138,2.31914802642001));
#546=CARTESIAN_POINT('',(12.,37.6778595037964,2.90156237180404));
#547=CARTESIAN_POINT('',(12.,38.2076589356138,3.19322244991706));
#548=CARTESIAN_POINT('',(12.,38.7372388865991,3.48528060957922));
#549=B_SPLINE_CURVE_WITH_KNOTS('',3,(#473,#474,#475,#476,#477,#478,#479,#480,#481,#482,#483,
#484,#485,#486,#487,#488,#489,#490,#491,#492,#493,#494,#495,#496,#497,#498,#499,#500,#501,#502,
#503,#504,#505,#506,#507,#508,#509,#510,#511,#512,#513,#514,#515,#516,#517,#518,#519,#520,#521,
#522,#523,#524,#525,#526,#527,#528,#529,#530,#531,#532,#533,#534,#535,#536,#537,#538,#539,#540,
#541,#542,#543,#544,#545,#546,#547,#548),.UNSPECIFIED.,.F.,.F.,(4,2,2,2,2,2,2,2,2,2,2,2,2,2,2,2,
2,2,2,2,2,2,2,2,2,2,2,2,2,2,2,2,2,2,2,2,2,4),(0.,0.875070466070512,1.75014960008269,
3.50056350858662,5.26038938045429,7.02013276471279,8.83673237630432,10.6535344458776,
12.4666396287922,14.2791774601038,15.1806042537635,16.0820128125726,16.9834042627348,
17.8847603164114,18.7742360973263,19.6636969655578,20.5531666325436,21.4426789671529,
22.6877912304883,23.9330690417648,26.4249371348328,27.6996687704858,28.974409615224,
30.2487503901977,31.5230678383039,33.5364846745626,35.5500809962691,37.564311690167,
39.5784777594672,41.5954439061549,43.6124232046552,45.6290428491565,47.645657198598,
51.2852237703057,54.9249735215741,58.5538713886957,60.3681986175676,62.1825234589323),.UNSPECIFIED.);
#550=CARTESIAN_POINT('',(12.,0.,-13.));
#551=VERTEX_POINT('',#550);
#552=EDGE_CURVE('E224',#460,#551,#549,.F.);
#553=ORIENTED_EDGE('',*,*,#552,.F.);
#554=ORIENTED_EDGE('',*,*,#461,.T.);
#555=ORIENTED_EDGE('',*,*,#311,.F.);
#556=ORIENTED_EDGE('',*,*,#352,.F.);
#557=DIRECTION('',(0.,0.,1.));
#558=VECTOR('',#557,1.);
#559=CARTESIAN_POINT('',(12.,-6.92820323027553,-13.));
#560=LINE('',#559,#558);
#561=CARTESIAN_POINT('',(12.,-6.92820323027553,-11.9282032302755));
#562=VERTEX_POINT('',#561);
#563=EDGE_CURVE('E237',#562,#349,#560,.T.);
#564=ORIENTED_EDGE('',*,*,#563,.F.);
#565=EDGE_CURVE('E218',#551,#562,#549,.F.);
#566=ORIENTED_EDGE('',*,*,#565,.F.);
#567=EDGE_LOOP('',(#553,#554,#555,#556,#564,#566));
#568=FACE_BOUND('',#567,.T.);
#569=ADVANCED_FACE('F208',(#568),#472,.T.);
#570=CARTESIAN_POINT('',(12.,-6.92820323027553,-13.));
#571=DIRECTION('',(0.5,-0.866025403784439,0.));
#572=DIRECTION('',(0.866025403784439,0.5,0.));
#573=AXIS2_PLACEMENT_3D('',#570,#571,#572);
#574=PLANE('',#573);
#575=CARTESIAN_POINT('',(12.0002,-6.92808776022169,-11.9281365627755));
#576=CARTESIAN_POINT('',(11.7364142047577,-7.08038456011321,-12.0160503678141));
#577=CARTESIAN_POINT('',(11.4716448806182,-7.23324920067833,-12.0999740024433));
#578=CARTESIAN_POINT('',(10.9399829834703,-7.54020434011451,-12.2587337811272));
#579=CARTESIAN_POINT('',(10.6730897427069,-7.69429522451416,-12.3335669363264));
#580=CARTESIAN_POINT('',(9.86810959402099,-8.15905073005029,-12.5429824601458));
#581=CARTESIAN_POINT('',(9.3268449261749,-8.47155003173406,-12.6620967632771));
#582=CARTESIAN_POINT('',(8.516867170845,-8.93919090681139,-12.8017689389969));
#583=CARTESIAN_POINT('',(8.25057389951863,-9.09293539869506,-12.8415562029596));
#584=CARTESIAN_POINT('',(7.71675440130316,-9.40113622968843,-12.9082766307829));
#585=CARTESIAN_POINT('',(7.44922815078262,-9.55559258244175,-12.9352095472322));
#586=CARTESIAN_POINT('',(6.91372963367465,-9.86476279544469,-12.9755314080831));
#587=CARTESIAN_POINT('',(6.64575827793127,-10.0194761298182,-12.9889364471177));
#588=CARTESIAN_POINT('',(6.10956726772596,-10.3290461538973,-13.0019169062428));
#589=CARTESIAN_POINT('',(5.84134762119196,-10.4839028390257,-13.0014927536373));
#590=CARTESIAN_POINT('',(5.33991062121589,-10.7734076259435,-12.9877799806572));
#591=CARTESIAN_POINT('',(5.10665750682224,-10.908076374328,-12.9761640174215));
#592=CARTESIAN_POINT('',(4.64068775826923,-11.1771041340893,-12.9426919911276));
#593=CARTESIAN_POINT('',(4.40797116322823,-11.3114631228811,-12.9208352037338));
#594=CARTESIAN_POINT('',(3.94320092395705,-11.5797983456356,-12.8672625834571));
#595=CARTESIAN_POINT('',(3.711147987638,-11.7137741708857,-12.8355386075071));
#596=CARTESIAN_POINT('',(3.24813003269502,-11.9810977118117,-12.7627882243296));
#597=CARTESIAN_POINT('',(3.01716508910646,-12.1144453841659,-12.7217611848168));
#598=CARTESIAN_POINT('',(2.31605804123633,-12.5192297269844,-12.5836883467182));
#599=CARTESIAN_POINT('',(1.84794625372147,-12.789494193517,-12.4728751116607));
#600=CARTESIAN_POINT('',(0.918702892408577,-13.3259930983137,-12.2213742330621));
#601=CARTESIAN_POINT('',(0.457559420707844,-13.5922344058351,-12.0807456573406));
#602=CARTESIAN_POINT('',(-0.00019999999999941,-13.8565219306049,-11.9281365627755));
#603=B_SPLINE_CURVE_WITH_KNOTS('',3,(#575,#576,#577,#578,#579,#580,#581,#582,#583,#584,#585,
#586,#587,#588,#589,#590,#591,#592,#593,#594,#595,#596,#597,#598,#599,#600,#601,#602),
.UNSPECIFIED.,.F.,.F.,(4,2,2,2,2,2,2,2,2,2,2,2,2,4),(0.,0.951004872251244,1.90232158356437,
3.80900466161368,4.7389455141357,5.66890426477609,6.59775529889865,7.5265776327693,
8.33514643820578,9.14377244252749,9.95306755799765,10.7624176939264,12.4167102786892,
14.0677556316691),.UNSPECIFIED.);
#604=CARTESIAN_POINT('',(5.99999999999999,-10.3923048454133,-13.));
#605=VERTEX_POINT('',#604);
#606=EDGE_CURVE('E55',#562,#605,#603,.T.);
#607=ORIENTED_EDGE('',*,*,#606,.F.);
#608=ORIENTED_EDGE('',*,*,#563,.T.);
#609=ORIENTED_EDGE('',*,*,#350,.F.);
#610=ORIENTED_EDGE('',*,*,#360,.F.);
#611=DIRECTION('',(0.,0.,1.));
#612=VECTOR('',#611,1.);
#613=CARTESIAN_POINT('',(0.,-13.856406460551,-13.));
#614=LINE('',#613,#612);
#615=CARTESIAN_POINT('',(0.,-13.856406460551,-11.9282032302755));
#616=VERTEX_POINT('',#615);
#617=EDGE_CURVE('E240',#616,#359,#614,.T.);
#618=ORIENTED_EDGE('',*,*,#617,.F.);
#619=EDGE_CURVE('E225',#605,#616,#603,.T.);
#620=ORIENTED_EDGE('',*,*,#619,.F.);
#621=EDGE_LOOP('',(#607,#608,#609,#610,#618,#620));
#622=FACE_BOUND('',#621,.T.);
#623=ADVANCED_FACE('F212',(#622),#574,.T.);
#624=CARTESIAN_POINT('',(-12.,-6.92820323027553,-13.));
#625=DIRECTION('',(-0.5,-0.866025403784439,0.));
#626=DIRECTION('',(0.866025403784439,-0.5,0.));
#627=AXIS2_PLACEMENT_3D('',#624,#625,#626);
#628=PLANE('',#627);
#629=CARTESIAN_POINT('',(0.0002,-13.8565219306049,-11.9281365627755));
#630=CARTESIAN_POINT('',(-0.263585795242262,-13.7042251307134,-12.0160503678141));
#631=CARTESIAN_POINT('',(-0.5283551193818,-13.5513604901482,-12.0999740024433));
#632=CARTESIAN_POINT('',(-1.06001701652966,-13.244405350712,-12.2587337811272));
#633=CARTESIAN_POINT('',(-1.32691025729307,-13.0903144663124,-12.3335669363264));
#634=CARTESIAN_POINT('',(-2.13189040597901,-12.6255589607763,-12.5429824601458));
#635=CARTESIAN_POINT('',(-2.6731550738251,-12.3130596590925,-12.6620967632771));
#636=CARTESIAN_POINT('',(-3.483132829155,-11.8454187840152,-12.8017689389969));
#637=CARTESIAN_POINT('',(-3.74942610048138,-11.6916742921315,-12.8415562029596));
#638=CARTESIAN_POINT('',(-4.28324559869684,-11.3834734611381,-12.9082766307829));
#639=CARTESIAN_POINT('',(-4.55077184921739,-11.2290171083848,-12.9352095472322));
#640=CARTESIAN_POINT('',(-5.08627036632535,-10.9198468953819,-12.9755314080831));
#641=CARTESIAN_POINT('',(-5.35424172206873,-10.7651335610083,-12.9889364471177));
#642=CARTESIAN_POINT('',(-5.89043273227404,-10.4555635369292,-13.0019169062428));
#643=CARTESIAN_POINT('',(-6.15865237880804,-10.3007068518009,-13.0014927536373));
#644=CARTESIAN_POINT('',(-6.66008937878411,-10.0112020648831,-12.9877799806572));
#645=CARTESIAN_POINT('',(-6.89334249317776,-9.87653331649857,-12.9761640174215));
#646=CARTESIAN_POINT('',(-7.35931224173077,-9.60750555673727,-12.9426919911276));
#647=CARTESIAN_POINT('',(-7.59202883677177,-9.47314656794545,-12.9208352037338));
#648=CARTESIAN_POINT('',(-8.05679907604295,-9.20481134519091,-12.8672625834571));
#649=CARTESIAN_POINT('',(-8.28885201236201,-9.07083551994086,-12.8355386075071));
#650=CARTESIAN_POINT('',(-8.75186996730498,-8.80351197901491,-12.7627882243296));
#651=CARTESIAN_POINT('',(-8.98283491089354,-8.67016430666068,-12.7217611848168));
#652=CARTESIAN_POINT('',(-9.68394195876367,-8.26537996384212,-12.5836883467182));
#653=CARTESIAN_POINT('',(-10.1520537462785,-7.99511549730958,-12.4728751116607));
#654=CARTESIAN_POINT('',(-11.0812971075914,-7.45861659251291,-12.2213742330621));
#655=CARTESIAN_POINT('',(-11.5424405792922,-7.19237528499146,-12.0807456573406));
#656=CARTESIAN_POINT('',(-12.0002,-6.92808776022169,-11.9281365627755));
#657=B_SPLINE_CURVE_WITH_KNOTS('',3,(#629,#630,#631,#632,#633,#634,#635,#636,#637,#638,#639,
#640,#641,#642,#643,#644,#645,#646,#647,#648,#649,#650,#651,#652,#653,#654,#655,#656),
.UNSPECIFIED.,.F.,.F.,(4,2,2,2,2,2,2,2,2,2,2,2,2,4),(0.,0.951004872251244,1.90232158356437,
3.80900466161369,4.7389455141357,5.66890426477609,6.59775529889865,7.5265776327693,
8.33514643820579,9.14377244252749,9.95306755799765,10.7624176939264,12.4167102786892,
14.0677556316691),.UNSPECIFIED.);
#658=CARTESIAN_POINT('',(-5.99999999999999,-10.3923048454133,-13.));
#659=VERTEX_POINT('',#658);
#660=EDGE_CURVE('E48',#616,#659,#657,.T.);
#661=ORIENTED_EDGE('',*,*,#660,.F.);
#662=ORIENTED_EDGE('',*,*,#617,.T.);
#663=ORIENTED_EDGE('',*,*,#392,.F.);
#664=ORIENTED_EDGE('',*,*,#399,.F.);
#665=DIRECTION('',(0.,0.,1.));
#666=VECTOR('',#665,1.);
#667=CARTESIAN_POINT('',(-12.,-6.92820323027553,-13.));
#668=LINE('',#667,#666);
#669=CARTESIAN_POINT('',(-12.,-6.92820323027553,-11.9282032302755));
#670=VERTEX_POINT('',#669);
#671=EDGE_CURVE('E243',#670,#398,#668,.T.);
#672=ORIENTED_EDGE('',*,*,#671,.F.);
#673=EDGE_CURVE('E284',#659,#670,#657,.T.);
#674=ORIENTED_EDGE('',*,*,#673,.F.);
#675=EDGE_LOOP('',(#661,#662,#663,#664,#672,#674));
#676=FACE_BOUND('',#675,.T.);
#677=ADVANCED_FACE('F274',(#676),#628,.T.);
#678=CARTESIAN_POINT('',(-12.,-6.92820323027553,-13.));
#679=DIRECTION('',(-1.,0.,0.));
#680=DIRECTION('',(0.,0.,1.));
#681=AXIS2_PLACEMENT_3D('',#678,#679,#680);
#682=PLANE('',#681);
#683=CARTESIAN_POINT('',(-12.,-18.6784608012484,-7.1104434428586));
#684=CARTESIAN_POINT('',(-12.,-18.4160847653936,-7.23788859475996));
#685=CARTESIAN_POINT('',(-12.,-18.1534026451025,-7.36470330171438));
#686=CARTESIAN_POINT('',(-12.,-17.6273623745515,-7.616929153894));
#687=CARTESIAN_POINT('',(-12.,-17.3640042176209,-7.74234028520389));
#688=CARTESIAN_POINT('',(-12.,-16.5727506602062,-8.11628694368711));
#689=CARTESIAN_POINT('',(-12.,-16.0437527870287,-8.36249841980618));
#690=CARTESIAN_POINT('',(-12.,-14.9793937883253,-8.84855811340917));
#691=CARTESIAN_POINT('',(-12.,-14.444013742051,-9.08836499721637));
#692=CARTESIAN_POINT('',(-12.,-13.3690190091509,-9.55825762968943));
#693=CARTESIAN_POINT('',(-12.,-12.82940452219,-9.78834383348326));
#694=CARTESIAN_POINT('',(-12.,-11.7275565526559,-10.2434635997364));
#695=CARTESIAN_POINT('',(-12.,-11.1651555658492,-10.4680937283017));
#696=CARTESIAN_POINT('',(-12.,-10.0337957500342,-10.9005191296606));
#697=CARTESIAN_POINT('',(-12.,-9.46483619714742,-11.1083125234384));
#698=CARTESIAN_POINT('',(-12.,-8.32051465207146,-11.5016575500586));
#699=CARTESIAN_POINT('',(-12.,-7.74516804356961,-11.687253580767));
#700=CARTESIAN_POINT('',(-12.,-6.58616859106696,-12.0303052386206));
#701=CARTESIAN_POINT('',(-12.,-6.0025184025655,-12.1877696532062));
#702=CARTESIAN_POINT('',(-12.,-5.12228513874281,-12.3967831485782));
#703=CARTESIAN_POINT('',(-12.,-4.82887752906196,-12.4617849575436));
#704=CARTESIAN_POINT('',(-12.,-4.24004478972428,-12.5819540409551));
#705=CARTESIAN_POINT('',(-12.,-3.94461970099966,-12.6371215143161));
#706=CARTESIAN_POINT('',(-12.,-3.35195163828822,-12.7366522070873));
#707=CARTESIAN_POINT('',(-12.,-3.05470869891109,-12.7810156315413));
#708=CARTESIAN_POINT('',(-12.,-2.45871340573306,-12.8580560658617));
#709=CARTESIAN_POINT('',(-12.,-2.15996111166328,-12.8907335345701));
#710=CARTESIAN_POINT('',(-12.,-1.56529773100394,-12.9433390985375));
#711=CARTESIAN_POINT('',(-12.,-1.26940109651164,-12.9634295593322));
#712=CARTESIAN_POINT('',(-12.,-0.677023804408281,-12.9910757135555));
#713=CARTESIAN_POINT('',(-12.,-0.380543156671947,-12.9986316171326));
#714=CARTESIAN_POINT('',(-12.,0.212474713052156,-13.001028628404));
#715=CARTESIAN_POINT('',(-12.,0.509011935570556,-12.9958696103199));
#716=CARTESIAN_POINT('',(-12.,1.10160312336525,-12.9729634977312));
#717=CARTESIAN_POINT('',(-12.,1.39765706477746,-12.9552157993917));
#718=CARTESIAN_POINT('',(-12.,2.1069630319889,-12.8979913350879));
#719=CARTESIAN_POINT('',(-12.,2.5197532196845,-12.8526643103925));
#720=CARTESIAN_POINT('',(-12.,3.34229647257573,-12.739992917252));
#721=CARTESIAN_POINT('',(-12.,3.75204912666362,-12.6726456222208));
#722=CARTESIAN_POINT('',(-12.,4.97625609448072,-12.4411424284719));
#723=CARTESIAN_POINT('',(-12.,5.78522177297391,-12.2475652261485));
#724=CARTESIAN_POINT('',(-12.,6.99520122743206,-11.9114742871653));
#725=CARTESIAN_POINT('',(-12.,7.40247585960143,-11.7902019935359));
#726=CARTESIAN_POINT('',(-12.,8.21306883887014,-11.5349690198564));
#727=CARTESIAN_POINT('',(-12.,8.61638715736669,-11.4010082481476));
#728=CARTESIAN_POINT('',(-12.,9.41919631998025,-11.1225558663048));
#729=CARTESIAN_POINT('',(-12.,9.81868832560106,-10.9780675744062));
#730=CARTESIAN_POINT('',(-12.,10.6143522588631,-10.6802698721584));
#731=CARTESIAN_POINT('',(-12.,11.0105242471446,-10.5269606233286));
#732=CARTESIAN_POINT('',(-12.,12.028867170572,-10.121932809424));
#733=CARTESIAN_POINT('',(-12.,12.6488461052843,-9.86470977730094));
#734=CARTESIAN_POINT('',(-12.,13.8828616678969,-9.33633807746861));
#735=CARTESIAN_POINT('',(-12.,14.4968977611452,-9.06518817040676));
#736=CARTESIAN_POINT('',(-12.,15.7203032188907,-8.51208578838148));
#737=CARTESIAN_POINT('',(-12.,16.3296710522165,-8.23012993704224));
#738=CARTESIAN_POINT('',(-12.,17.5444335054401,-7.65786008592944));
#739=CARTESIAN_POINT('',(-12.,18.1498282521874,-7.36754635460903));
#740=CARTESIAN_POINT('',(-12.,19.3582283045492,-6.7798843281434));
#741=CARTESIAN_POINT('',(-12.,19.9612291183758,-6.48252681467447));
#742=CARTESIAN_POINT('',(-12.,21.1645717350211,-5.88247798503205));
#743=CARTESIAN_POINT('',(-12.,21.764913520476,-5.57978663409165));
#744=CARTESIAN_POINT('',(-12.,22.9632839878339,-4.97012650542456));
#745=CARTESIAN_POINT('',(-12.,23.5613130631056,-4.6631585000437));
#746=CARTESIAN_POINT('',(-12.,24.7555248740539,-4.04565935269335));
#747=CARTESIAN_POINT('',(-12.,25.3517076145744,-3.73512822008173));
#748=CARTESIAN_POINT('',(-12.,27.0217096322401,-2.86002109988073));
#749=CARTESIAN_POINT('',(-12.,28.0937859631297,-2.29211945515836));
#750=CARTESIAN_POINT('',(-12.,30.2342410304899,-1.14927758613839));
#751=CARTESIAN_POINT('',(-12.,31.3026195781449,-0.574337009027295));
#752=CARTESIAN_POINT('',(-12.,33.4333268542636,0.579117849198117));
#753=CARTESIAN_POINT('',(-12.,34.4956641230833,1.15761636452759));
#754=CARTESIAN_POINT('',(-12.,36.0874641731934,2.02839376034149));
#755=CARTESIAN_POINT('',(-12.,36.6177621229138,2.31914802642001));
#756=CARTESIAN_POINT('',(-12.,37.6778595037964,2.90156237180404));
#757=CARTESIAN_POINT('',(-12.,38.2076589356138,3.19322244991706));
#758=CARTESIAN_POINT('',(-12.,38.7372388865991,3.48528060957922));
#759=B_SPLINE_CURVE_WITH_KNOTS('',3,(#683,#684,#685,#686,#687,#688,#689,#690,#691,#692,#693,
#694,#695,#696,#697,#698,#699,#700,#701,#702,#703,#704,#705,#706,#707,#708,#709,#710,#711,#712,
#713,#714,#715,#716,#717,#718,#719,#720,#721,#722,#723,#724,#725,#726,#727,#728,#729,#730,#731,
#732,#733,#734,#735,#736,#737,#738,#739,#740,#741,#742,#743,#744,#745,#746,#747,#748,#749,#750,
#751,#752,#753,#754,#755,#756,#757,#758),.UNSPECIFIED.,.F.,.F.,(4,2,2,2,2,2,2,2,2,2,2,2,2,2,2,2,
2,2,2,2,2,2,2,2,2,2,2,2,2,2,2,2,2,2,2,2,2,4),(0.,0.875070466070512,1.75014960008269,
3.50056350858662,5.26038938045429,7.02013276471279,8.83673237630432,10.6535344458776,
12.4666396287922,14.2791774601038,15.1806042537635,16.0820128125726,16.9834042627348,
17.8847603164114,18.7742360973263,19.6636969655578,20.5531666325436,21.4426789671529,
22.6877912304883,23.9330690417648,26.4249371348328,27.6996687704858,28.974409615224,
30.2487503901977,31.5230678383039,33.5364846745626,35.5500809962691,37.564311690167,
39.5784777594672,41.5954439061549,43.6124232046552,45.6290428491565,47.645657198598,
51.2852237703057,54.9249735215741,58.5538713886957,60.3681986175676,62.1825234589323),.UNSPECIFIED.);
#760=CARTESIAN_POINT('',(-12.,0.,-13.));
#761=VERTEX_POINT('',#760);
#762=EDGE_CURVE('E279',#670,#761,#759,.T.);
#763=ORIENTED_EDGE('',*,*,#762,.F.);
#764=ORIENTED_EDGE('',*,*,#671,.T.);
#765=ORIENTED_EDGE('',*,*,#402,.F.);
#766=ORIENTED_EDGE('',*,*,#156,.F.);
#767=DIRECTION('',(0.,0.,1.));
#768=VECTOR('',#767,1.);
#769=CARTESIAN_POINT('',(-12.,6.92820323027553,-13.));
#770=LINE('',#769,#768);
#771=CARTESIAN_POINT('',(-12.,6.92820323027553,-11.9282032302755));
#772=VERTEX_POINT('',#771);
#773=EDGE_CURVE('E246',#772,#155,#770,.T.);
#774=ORIENTED_EDGE('',*,*,#773,.F.);
#775=EDGE_CURVE('E281',#761,#772,#759,.T.);
#776=ORIENTED_EDGE('',*,*,#775,.F.);
#777=EDGE_LOOP('',(#763,#764,#765,#766,#774,#776));
#778=FACE_BOUND('',#777,.T.);
#779=ADVANCED_FACE('F277',(#778),#682,.T.);
#780=CARTESIAN_POINT('',(-12.,6.92820323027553,-13.));
#781=DIRECTION('',(-0.5,0.866025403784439,0.));
#782=DIRECTION('',(-0.866025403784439,-0.5,0.));
#783=AXIS2_PLACEMENT_3D('',#780,#781,#782);
#784=PLANE('',#783);
#785=CARTESIAN_POINT('',(-12.0002,6.92808776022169,-11.9281365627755));
#786=CARTESIAN_POINT('',(-11.7364142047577,7.08038456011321,-12.0160503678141));
#787=CARTESIAN_POINT('',(-11.4716448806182,7.23324920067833,-12.0999740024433));
#788=CARTESIAN_POINT('',(-10.9399829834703,7.54020434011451,-12.2587337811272));
#789=CARTESIAN_POINT('',(-10.6730897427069,7.69429522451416,-12.3335669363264));
#790=CARTESIAN_POINT('',(-9.86810959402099,8.15905073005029,-12.5429824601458));
#791=CARTESIAN_POINT('',(-9.3268449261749,8.47155003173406,-12.6620967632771));
#792=CARTESIAN_POINT('',(-8.516867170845,8.93919090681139,-12.8017689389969));
#793=CARTESIAN_POINT('',(-8.25057389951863,9.09293539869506,-12.8415562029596));
#794=CARTESIAN_POINT('',(-7.71675440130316,9.40113622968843,-12.9082766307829));
#795=CARTESIAN_POINT('',(-7.44922815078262,9.55559258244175,-12.9352095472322));
#796=CARTESIAN_POINT('',(-6.91372963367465,9.86476279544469,-12.9755314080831));
#797=CARTESIAN_POINT('',(-6.64575827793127,10.0194761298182,-12.9889364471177));
#798=CARTESIAN_POINT('',(-6.10956726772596,10.3290461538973,-13.0019169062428));
#799=CARTESIAN_POINT('',(-5.84134762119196,10.4839028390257,-13.0014927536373));
#800=CARTESIAN_POINT('',(-5.33991062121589,10.7734076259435,-12.9877799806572));
#801=CARTESIAN_POINT('',(-5.10665750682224,10.908076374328,-12.9761640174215));
#802=CARTESIAN_POINT('',(-4.64068775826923,11.1771041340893,-12.9426919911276));
#803=CARTESIAN_POINT('',(-4.40797116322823,11.3114631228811,-12.9208352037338));
#804=CARTESIAN_POINT('',(-3.94320092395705,11.5797983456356,-12.8672625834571));
#805=CARTESIAN_POINT('',(-3.711147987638,11.7137741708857,-12.8355386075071));
#806=CARTESIAN_POINT('',(-3.24813003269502,11.9810977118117,-12.7627882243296));
#807=CARTESIAN_POINT('',(-3.01716508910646,12.1144453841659,-12.7217611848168));
#808=CARTESIAN_POINT('',(-2.31605804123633,12.5192297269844,-12.5836883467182));
#809=CARTESIAN_POINT('',(-1.84794625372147,12.789494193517,-12.4728751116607));
#810=CARTESIAN_POINT('',(-0.918702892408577,13.3259930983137,-12.2213742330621));
#811=CARTESIAN_POINT('',(-0.457559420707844,13.5922344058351,-12.0807456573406));
#812=CARTESIAN_POINT('',(0.00019999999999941,13.8565219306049,-11.9281365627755));
#813=B_SPLINE_CURVE_WITH_KNOTS('',3,(#785,#786,#787,#788,#789,#790,#791,#792,#793,#794,#795,
#796,#797,#798,#799,#800,#801,#802,#803,#804,#805,#806,#807,#808,#809,#810,#811,#812),
.UNSPECIFIED.,.F.,.F.,(4,2,2,2,2,2,2,2,2,2,2,2,2,4),(0.,0.951004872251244,1.90232158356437,
3.80900466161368,4.7389455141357,5.66890426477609,6.59775529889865,7.5265776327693,
8.33514643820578,9.14377244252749,9.95306755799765,10.7624176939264,12.4167102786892,
14.0677556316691),.UNSPECIFIED.);
#814=CARTESIAN_POINT('',(-6.,10.3923048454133,-13.));
#815=VERTEX_POINT('',#814);
#816=EDGE_CURVE('E286',#772,#815,#813,.T.);
#817=ORIENTED_EDGE('',*,*,#816,.F.);
#818=ORIENTED_EDGE('',*,*,#773,.T.);
#819=ORIENTED_EDGE('',*,*,#188,.F.);
#820=ORIENTED_EDGE('',*,*,#226,.F.);
#821=ORIENTED_EDGE('',*,*,#451,.F.);
#822=EDGE_CURVE('E265',#815,#442,#813,.T.);
#823=ORIENTED_EDGE('',*,*,#822,.F.);
#824=EDGE_LOOP('',(#817,#818,#819,#820,#821,#823));
#825=FACE_BOUND('',#824,.T.);
#826=ADVANCED_FACE('F298',(#825),#784,.T.);
#827=CARTESIAN_POINT('',(0.,0.,-6.5));
#828=DIRECTION('',(0.,0.,1.));
#829=DIRECTION('',(1.,0.,0.));
#830=AXIS2_PLACEMENT_3D('',#827,#828,#829);
#831=CONICAL_SURFACE('',#830,23.2583302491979,1.0471975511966);
#832=ORIENTED_EDGE('',*,*,#775,.T.);
#833=ORIENTED_EDGE('',*,*,#816,.T.);
#834=CARTESIAN_POINT('',(0.,0.,-13.));
#835=DIRECTION('',(0.,0.,-1.));
#836=DIRECTION('',(-1.,0.,0.));
#837=AXIS2_PLACEMENT_3D('',#834,#835,#836);
#838=CIRCLE('',#837,12.);
#839=EDGE_CURVE('E323',#761,#815,#838,.T.);
#840=ORIENTED_EDGE('',*,*,#839,.F.);
#841=EDGE_LOOP('',(#832,#833,#840));
#842=FACE_BOUND('',#841,.T.);
#843=ADVANCED_FACE('F183',(#842),#831,.T.);
#844=ORIENTED_EDGE('',*,*,#445,.T.);
#845=CARTESIAN_POINT('',(0.,0.,-13.));
#846=DIRECTION('',(0.,0.,-1.));
#847=DIRECTION('',(-1.,0.,0.));
#848=AXIS2_PLACEMENT_3D('',#845,#846,#847);
#849=CIRCLE('',#848,12.);
#850=EDGE_CURVE('E41',#444,#815,#849,.F.);
#851=ORIENTED_EDGE('',*,*,#850,.T.);
#852=ORIENTED_EDGE('',*,*,#822,.T.);
#853=EDGE_LOOP('',(#844,#851,#852));
#854=FACE_BOUND('',#853,.T.);
#855=ADVANCED_FACE('F308',(#854),#831,.T.);
#856=ORIENTED_EDGE('',*,*,#463,.T.);
#857=ORIENTED_EDGE('',*,*,#552,.T.);
#858=EDGE_CURVE('E253',#551,#444,#849,.F.);
#859=ORIENTED_EDGE('',*,*,#858,.T.);
#860=EDGE_LOOP('',(#856,#857,#859));
#861=FACE_BOUND('',#860,.T.);
#862=ADVANCED_FACE('F335',(#861),#831,.T.);
#863=ORIENTED_EDGE('',*,*,#565,.T.);
#864=ORIENTED_EDGE('',*,*,#606,.T.);
#865=EDGE_CURVE('E340',#605,#551,#849,.F.);
#866=ORIENTED_EDGE('',*,*,#865,.T.);
#867=EDGE_LOOP('',(#863,#864,#866));
#868=FACE_BOUND('',#867,.T.);
#869=ADVANCED_FACE('F338',(#868),#831,.T.);
#870=ORIENTED_EDGE('',*,*,#619,.T.);
#871=ORIENTED_EDGE('',*,*,#660,.T.);
#872=EDGE_CURVE('E40',#659,#605,#849,.F.);
#873=ORIENTED_EDGE('',*,*,#872,.T.);
#874=EDGE_LOOP('',(#870,#871,#873));
#875=FACE_BOUND('',#874,.T.);
#876=ADVANCED_FACE('F342',(#875),#831,.T.);
#877=ORIENTED_EDGE('',*,*,#673,.T.);
#878=ORIENTED_EDGE('',*,*,#762,.T.);
#879=EDGE_CURVE('E11',#761,#659,#849,.F.);
#880=ORIENTED_EDGE('',*,*,#879,.T.);
#881=EDGE_LOOP('',(#877,#878,#880));
#882=FACE_BOUND('',#881,.T.);
#883=ADVANCED_FACE('F310',(#882),#831,.T.);
#884=CARTESIAN_POINT('',(-12.,20.7846096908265,-13.));
#885=DIRECTION('',(0.,0.,-1.));
#886=DIRECTION('',(-1.,0.,0.));
#887=AXIS2_PLACEMENT_3D('',#884,#885,#886);
#888=PLANE('',#887);
#889=CARTESIAN_POINT('',(0.,0.,-13.));
#890=DIRECTION('',(0.,0.,1.));
#891=DIRECTION('',(1.,0.,0.));
#892=AXIS2_PLACEMENT_3D('',#889,#890,#891);
#893=CIRCLE('',#892,8.);
#894=CARTESIAN_POINT('',(8.,0.,-13.));
#895=VERTEX_POINT('',#894);
#896=EDGE_CURVE('E320',#895,#895,#893,.T.);
#897=ORIENTED_EDGE('',*,*,#896,.T.);
#898=EDGE_LOOP('',(#897));
#899=FACE_BOUND('',#898,.T.);
#900=ORIENTED_EDGE('',*,*,#879,.F.);
#901=ORIENTED_EDGE('',*,*,#839,.T.);
#902=ORIENTED_EDGE('',*,*,#850,.F.);
#903=ORIENTED_EDGE('',*,*,#858,.F.);
#904=ORIENTED_EDGE('',*,*,#865,.F.);
#905=ORIENTED_EDGE('',*,*,#872,.F.);
#906=EDGE_LOOP('',(#900,#901,#902,#903,#904,#905));
#907=FACE_BOUND('',#906,.T.);
#908=ADVANCED_FACE('F214',(#899,#907),#888,.T.);
#909=CARTESIAN_POINT('',(0.,0.,-13.));
#910=DIRECTION('',(0.,0.,1.));
#911=DIRECTION('',(1.,0.,0.));
#912=AXIS2_PLACEMENT_3D('',#909,#910,#911);
#913=CYLINDRICAL_SURFACE('',#912,8.);
#914=ORIENTED_EDGE('',*,*,#896,.F.);
#915=EDGE_LOOP('',(#914));
#916=FACE_BOUND('',#915,.T.);
#917=ORIENTED_EDGE('',*,*,#31,.T.);
#918=EDGE_LOOP('',(#917));
#919=FACE_BOUND('',#918,.T.);
#920=ADVANCED_FACE('F182',(#916,#919),#913,.F.);
#921=CLOSED_SHELL('',(#71,#192,#231,#318,#357,#396,#406,#467,#569,#623,#677,#779,#826,#843,#855,
#862,#869,#876,#883,#908,#920));
#922=MANIFOLD_SOLID_BREP('B2',#921);
#923=ADVANCED_BREP_SHAPE_REPRESENTATION('',(#18,#922),#14);
#924=SHAPE_DEFINITION_REPRESENTATION(#9,#923);
ENDSEC;
END-ISO-10303-21;
